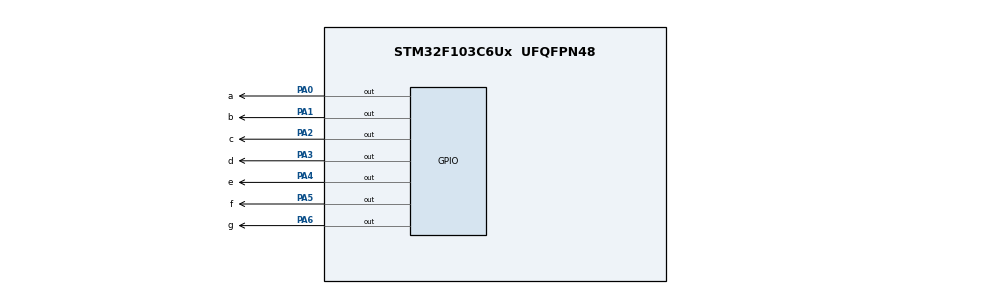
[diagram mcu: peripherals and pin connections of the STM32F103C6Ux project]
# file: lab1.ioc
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Mcu.Family=STM32F1
Mcu.Name=STM32F103C6Ux
Mcu.Package=UFQFPN48
NVIC.PriorityGroup=NVIC_PRIORITYGROUP_4
PA0-WKUP.GPIO_Label=a
PA0-WKUP.Signal=GPIO_Output
PA1.GPIO_Label=b
PA1.Signal=GPIO_Output
PA2.GPIO_Label=c
PA2.Signal=GPIO_Output
PA3.GPIO_Label=d
PA3.Signal=GPIO_Output
PA4.GPIO_Label=e
PA4.Signal=GPIO_Output
PA5.GPIO_Label=f
PA5.Signal=GPIO_Output
PA6.GPIO_Label=g
PA6.Signal=GPIO_Output
ProjectManager.HeapSize=0x200
ProjectManager.StackSize=0x400
ProjectManager.TargetToolchain=STM32CubeIDE
RCC.APB1Freq_Value=8000000
RCC.APB2Freq_Value=8000000
VP_SYS_VS_ND.Mode=No_Debug
board=custom

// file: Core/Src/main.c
/* USER CODE BEGIN Header */
/**
  ******************************************************************************
  * @file           : main.c
  * @brief          : Main program body
  ******************************************************************************
  * @attention
  *
  * <h2><center>&copy; Copyright (c) 2023 STMicroelectronics.
  * All rights reserved.</center></h2>
  *
  * This software component is licensed by ST under BSD 3-Clause license,
  * the "License"; You may not use this file except in compliance with the
  * License. You may obtain a copy of the License at:
  *                        opensource.org/licenses/BSD-3-Clause
  *
  ******************************************************************************
  */
/* USER CODE END Header */
#include "main.h"

void SystemClock_Config(void);
static void MX_GPIO_Init(void);

int main(void)
{

  /* MCU Configuration--------------------------------------------------------*/

  /* Reset of all peripherals, Initializes the Flash interface and the Systick. */
  HAL_Init();

  /* Configure the system clock */
  SystemClock_Config();

  /* Initialize all configured peripherals */
  MX_GPIO_Init();

  /* Infinite loop */
  /* USER CODE BEGIN WHILE */
  void turnOffAllLEDs() {
      HAL_GPIO_WritePin(GPIOA, ZERO_Pin | ONE_Pin | TWO_Pin | THREE_Pin |
    		  FOUR_Pin | FIVE_Pin | SIX_Pin |SEVEN_Pin |
			  EI_Pin | NINE_Pin | TEN_Pin | ELV_Pin, GPIO_PIN_SET);
  }
  void turnOnAllLEDs(void) {
      HAL_GPIO_WritePin(GPIOA, ZERO_Pin | ONE_Pin | TWO_Pin | THREE_Pin |
    		  FOUR_Pin | FIVE_Pin | SIX_Pin |SEVEN_Pin |
			  EI_Pin | NINE_Pin | TEN_Pin | ELV_Pin, GPIO_PIN_RESET);
  }
  void setNumberOnClock(int num) {
	  if(num >= 0 && num <= 11){
		 /turnOffAllLEDs();
		  switch(num){
		  case 0:
			  HAL_GPIO_WritePin(ZERO_GPIO_Port, ZERO_Pin, GPIO_PIN_RESET);
			  break;
		  case 1:
			  HAL_GPIO_WritePin(ONE_GPIO_Port, ONE_Pin, GPIO_PIN_RESET);
			  break;
		  case 2:
			  HAL_GPIO_WritePin(TWO_GPIO_Port, TWO_Pin, GPIO_PIN_RESET);
			  break;
		  case 3:
			  HAL_GPIO_WritePin(THREE_GPIO_Port, THREE_Pin, GPIO_PIN_RESET);
			  break;
		  case 4:
			  HAL_GPIO_WritePin(FOUR_GPIO_Port, FOUR_Pin, GPIO_PIN_RESET);
			  break;
		  case 5:
			  HAL_GPIO_WritePin(FIVE_GPIO_Port, FIVE_Pin, GPIO_PIN_RESET);
			  break;
		  case 6:
			  HAL_GPIO_WritePin(SIX_GPIO_Port, SIX_Pin, GPIO_PIN_RESET);
			  break;
		  case 7:
			  HAL_GPIO_WritePin(SEVEN_GPIO_Port, SEVEN_Pin, GPIO_PIN_RESET);
			  break;
		  case 8:
			  HAL_GPIO_WritePin(EI_GPIO_Port, EI_Pin, GPIO_PIN_RESET);
			  break;
		  case 9:
			  HAL_GPIO_WritePin(NINE_GPIO_Port, NINE_Pin, GPIO_PIN_RESET);
			  break;
		  case 10:
			  HAL_GPIO_WritePin(TEN_GPIO_Port, TEN_Pin, GPIO_PIN_RESET);
			  break;
		  case 11:
			  HAL_GPIO_WritePin(ELV_GPIO_Port, ELV_Pin, GPIO_PIN_RESET);
			  break;
		  }
	  }
  }
  void setNumberOnClock60(int num) {
	  if(num >= 0 && num <= 60){
		  //turnOffAllLEDs();
		  switch(num){
		  case 0:
			  HAL_GPIO_WritePin(ZERO_GPIO_Port, ZERO_Pin, GPIO_PIN_RESET);
			  break;
		  case 5:
			  HAL_GPIO_WritePin(ONE_GPIO_Port, ONE_Pin, GPIO_PIN_RESET);
			  break;
		  case 10:
			  HAL_GPIO_WritePin(TWO_GPIO_Port, TWO_Pin, GPIO_PIN_RESET);
			  break;
		  case 15:
			  HAL_GPIO_WritePin(THREE_GPIO_Port, THREE_Pin, GPIO_PIN_RESET);
			  break;
		  case 20:
			  HAL_GPIO_WritePin(FOUR_GPIO_Port, FOUR_Pin, GPIO_PIN_RESET);
			  break;
		  case 25:
			  HAL_GPIO_WritePin(FIVE_GPIO_Port, FIVE_Pin, GPIO_PIN_RESET);
			  break;
		  case 30:
			  HAL_GPIO_WritePin(SIX_GPIO_Port, SIX_Pin, GPIO_PIN_RESET);
			  break;
		  case 35:
			  HAL_GPIO_WritePin(SEVEN_GPIO_Port, SEVEN_Pin, GPIO_PIN_RESET);
			  break;
		  case 40:
			  HAL_GPIO_WritePin(EI_GPIO_Port, EI_Pin, GPIO_PIN_RESET);
			  break;
		  case 45:
			  HAL_GPIO_WritePin(NINE_GPIO_Port, NINE_Pin, GPIO_PIN_RESET);
			  break;
		  case 50:
			  HAL_GPIO_WritePin(TEN_GPIO_Port, TEN_Pin, GPIO_PIN_RESET);
			  break;
		  case 55:
			  HAL_GPIO_WritePin(ELV_GPIO_Port, ELV_Pin, GPIO_PIN_RESET);
			  break;
		  }
	  }
  }
  void clearNumberOnClock(int num){
	  if(num >= 0 && num <= 11){
		  turnOnAllLEDs();
		  switch(num){
		  case 0:
			  HAL_GPIO_WritePin(ZERO_GPIO_Port, ZERO_Pin, GPIO_PIN_SET);
			  break;
		  case 1:
			  HAL_GPIO_WritePin(ONE_GPIO_Port, ONE_Pin, GPIO_PIN_SET);
			  break;
		  case 2:
			  HAL_GPIO_WritePin(TWO_GPIO_Port, TWO_Pin, GPIO_PIN_SET);
			  break;
		  case 3:
			  HAL_GPIO_WritePin(THREE_GPIO_Port, THREE_Pin, GPIO_PIN_SET);
			  break;
		  case 4:
			  HAL_GPIO_WritePin(FOUR_GPIO_Port, FOUR_Pin, GPIO_PIN_SET);
			  break;
		  case 5:
			  HAL_GPIO_WritePin(FIVE_GPIO_Port, FIVE_Pin, GPIO_PIN_SET);
			  break;
		  case 6:
			  HAL_GPIO_WritePin(SIX_GPIO_Port, SIX_Pin, GPIO_PIN_SET);
			  break;
		  case 7:
			  HAL_GPIO_WritePin(SEVEN_GPIO_Port, SEVEN_Pin, GPIO_PIN_SET);
			  break;
		  case 8:
			  HAL_GPIO_WritePin(EI_GPIO_Port, EI_Pin, GPIO_PIN_SET);
			  break;
		  case 9:
			  HAL_GPIO_WritePin(NINE_GPIO_Port, NINE_Pin, GPIO_PIN_SET);
			  break;
		  case 10:
			  HAL_GPIO_WritePin(TEN_GPIO_Port, TEN_Pin, GPIO_PIN_SET);
			  break;
		  case 11:
			  HAL_GPIO_WritePin(ELV_GPIO_Port, ELV_Pin, GPIO_PIN_SET);
			  break;
		  }
	  }
  }

//ham support
int roundDownToNearest5(int num) {
      int quotient = num / 5;
      int roundedNum = quotient * 5;
      return roundedNum;
  }
int hourChange(int hour){
	int validHour;
	if(hour > 11){
		if(hour == 12 || hour==24){
			validHour=0;
		}
		validHour=hour-12;
	}
	return validHour;
}
  //int hour = 16;
  //int min = 55;
  int sec = 0;
  while (1)
  {
	  ///*
	    //display
	    turnOffAllLEDs();
	    setNumberOnClock(sec);

	    //logic
	    sec++;
	    if(sec>11){
	    	sec=0;
	    	}

	    HAL_Delay(1000);
	    //*/
/* test ham ex789
 * clearNumberOnClock(counter);
	  counter++;
	  if(counter > 11) counter=0;
	  HAL_Delay(1000);
	  turnOffAllLEDs();
*/
    /* USER CODE END WHILE */

  }
}

void SystemClock_Config(void)
{
  RCC_OscInitTypeDef RCC_OscInitStruct = {0};
  RCC_ClkInitTypeDef RCC_ClkInitStruct = {0};

  /** Initializes the RCC Oscillators according to the specified parameters
  * in the RCC_OscInitTypeDef structure.
  */
  RCC_OscInitStruct.OscillatorType = RCC_OSCILLATORTYPE_HSI;
  RCC_OscInitStruct.HSIState = RCC_HSI_ON;
  RCC_OscInitStruct.HSICalibrationValue = RCC_HSICALIBRATION_DEFAULT;
  RCC_OscInitStruct.PLL.PLLState = RCC_PLL_NONE;
  if (HAL_RCC_OscConfig(&RCC_OscInitStruct) != HAL_OK)
  {
    Error_Handler();
  }
  /** Initializes the CPU, AHB and APB buses clocks
  */
  RCC_ClkInitStruct.ClockType = RCC_CLOCKTYPE_HCLK|RCC_CLOCKTYPE_SYSCLK
                              |RCC_CLOCKTYPE_PCLK1|RCC_CLOCKTYPE_PCLK2;
  RCC_ClkInitStruct.SYSCLKSource = RCC_SYSCLKSOURCE_HSI;
  RCC_ClkInitStruct.AHBCLKDivider = RCC_SYSCLK_DIV1;
  RCC_ClkInitStruct.APB1CLKDivider = RCC_HCLK_DIV1;
  RCC_ClkInitStruct.APB2CLKDivider = RCC_HCLK_DIV1;

  if (HAL_RCC_ClockConfig(&RCC_ClkInitStruct, FLASH_LATENCY_0) != HAL_OK)
  {
    Error_Handler();
  }
}

static void MX_GPIO_Init(void)
{
  GPIO_InitTypeDef GPIO_InitStruct = {0};

  /* GPIO Ports Clock Enable */
  __HAL_RCC_GPIOA_CLK_ENABLE();

  /*Configure GPIO pin Output Level */
  HAL_GPIO_WritePin(GPIOA, ZERO_Pin|ONE_Pin|TWO_Pin|THREE_Pin
                          |FOUR_Pin|FIVE_Pin|SIX_Pin|SEVEN_Pin
                          |EI_Pin|NINE_Pin|TEN_Pin|ELV_Pin, GPIO_PIN_RESET);

  /*Configure GPIO pins : ZERO_Pin ONE_Pin TWO_Pin THREE_Pin
                           FOUR_Pin FIVE_Pin SIX_Pin SEVEN_Pin
                           EI_Pin NINE_Pin TEN_Pin ELV_Pin */
  GPIO_InitStruct.Pin = ZERO_Pin|ONE_Pin|TWO_Pin|THREE_Pin
                          |FOUR_Pin|FIVE_Pin|SIX_Pin|SEVEN_Pin
                          |EI_Pin|NINE_Pin|TEN_Pin|ELV_Pin;
  GPIO_InitStruct.Mode = GPIO_MODE_OUTPUT_PP;
  GPIO_InitStruct.Pull = GPIO_NOPULL;
  GPIO_InitStruct.Speed = GPIO_SPEED_FREQ_LOW;
  HAL_GPIO_Init(GPIOA, &GPIO_InitStruct);

}

void Error_Handler(void)
{
  __disable_irq();
  while (1)
  {
  }
}

/************************ (C) COPYRIGHT STMicroelectronics *****END OF FILE****/
